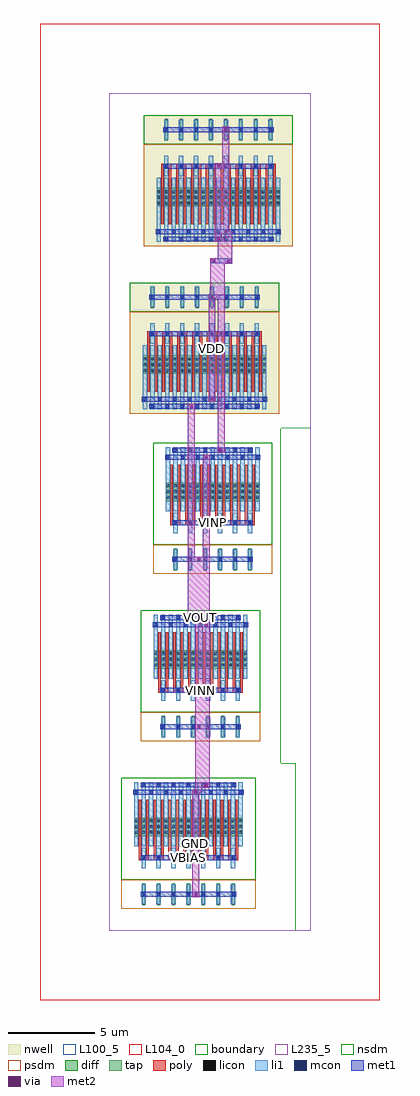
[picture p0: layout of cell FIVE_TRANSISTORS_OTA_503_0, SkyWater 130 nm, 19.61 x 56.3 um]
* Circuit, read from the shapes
.subckt FIVE_TRANSISTORS_OTA_503_0 GND VBIAS VDD VINN VINP VOUT
XM1 n1 VBIAS GND GND sky130_fd_pr__nfet_01v8 w=1.05 l=0.15 m=14
XM2 VOUT VINN n1 GND sky130_fd_pr__nfet_01v8 w=1.05 l=0.15 m=12
XM3 n2 VINP n1 GND sky130_fd_pr__nfet_01v8 w=1.05 l=0.15 m=12
XM4 VOUT n2 VDD VDD sky130_fd_pr__pfet_01v8 w=1.05 l=0.15 m=16
XM5 n2 n2 VDD VDD sky130_fd_pr__pfet_01v8 w=1.05 l=0.15 m=16
.ends

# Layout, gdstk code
from math import pi, radians
import gdstk
lib = gdstk.Library(unit=1e-6, precision=1e-09)
def R(c, l, rs):  # rectangles x0, y0, x1, y1
    for r in rs: c.add(gdstk.rectangle(r[:2], r[2:], *l))
def A(c, l, x, y, w, h, nx, ny, dx, dy):  # array of equal rectangles
    R(c, l, [(x+i*dx, y+j*dy, x+i*dx+w, y+j*dy+h) for i in range(nx) for j in range(ny)])
def P(c, l, *ps):  # polygons
    for p in ps: c.add(gdstk.Polygon(p, *l))
nwell = (64, 20)
diff = (65, 20)
tap = (65, 44)
poly = (66, 20)
licon = (66, 44)
li1 = (67, 20)
mcon = (67, 44)
met1 = (68, 20)
via = (68, 44)
met2 = (69, 20)
nsdm = (93, 44)
psdm = (94, 20)
L100_5 = (100, 5)
L104_0 = (104, 0)
boundary = (235, 4)
L235_5 = (235, 5)

dcl_pmos_s_4858765_x8_y1 = lib.new_cell('DCL_PMOS_S_4858765_X8_Y1_1746772025')
R(dcl_pmos_s_4858765_x8_y1, nwell, [(1.99,0.84,10.59,8.4)])
R(dcl_pmos_s_4858765_x8_y1, diff, [(2.725,3.15,9.855,4.2)])
A(dcl_pmos_s_4858765_x8_y1, tap, 3.195, 6.915, 0.17, 1.29, 8, 1, 0.86, 0)
A(dcl_pmos_s_4858765_x8_y1, poly, 2.99, 2.1, 0.15, 3.36, 16, 1, 0.43, 0)
A(dcl_pmos_s_4858765_x8_y1, poly, 2.99, 5.325, 0.58, 0.27, 8, 1, 0.86, 0)
A(dcl_pmos_s_4858765_x8_y1, licon, 2.765, 3.23, 0.17, 0.17, 3, 3, 0.43, 0.34)
A(dcl_pmos_s_4858765_x8_y1, licon, 3.625, 3.23, 0.17, 0.17, 3, 3, 0.43, 0.34)
A(dcl_pmos_s_4858765_x8_y1, licon, 4.485, 3.23, 0.17, 0.17, 3, 3, 0.43, 0.34)
A(dcl_pmos_s_4858765_x8_y1, licon, 5.345, 3.23, 0.17, 0.17, 3, 3, 0.43, 0.34)
A(dcl_pmos_s_4858765_x8_y1, licon, 6.205, 3.23, 0.17, 0.17, 3, 3, 0.43, 0.34)
A(dcl_pmos_s_4858765_x8_y1, licon, 7.065, 3.23, 0.17, 0.17, 3, 3, 0.43, 0.34)
A(dcl_pmos_s_4858765_x8_y1, licon, 7.925, 3.23, 0.17, 0.17, 3, 3, 0.43, 0.34)
A(dcl_pmos_s_4858765_x8_y1, licon, 8.785, 3.23, 0.17, 0.17, 3, 3, 0.43, 0.34)
A(dcl_pmos_s_4858765_x8_y1, licon, 3.195, 5.375, 0.17, 0.17, 8, 2, 0.86, 2.1)
A(dcl_pmos_s_4858765_x8_y1, li1, 2.725, 1.09, 0.25, 3.7, 17, 1, 0.43, 0)
A(dcl_pmos_s_4858765_x8_y1, li1, 3.155, 4.87, 0.25, 1.18, 8, 2, 0.86, 2.1)
A(dcl_pmos_s_4858765_x8_y1, mcon, 3.195, 1.175, 0.17, 0.17, 8, 2, 0.86, 4.2)
A(dcl_pmos_s_4858765_x8_y1, mcon, 2.765, 1.595, 0.17, 0.17, 9, 1, 0.86, 0)
A(dcl_pmos_s_4858765_x8_y1, mcon, 3.195, 7.475, 0.17, 0.17, 8, 1, 0.86, 0)
R(dcl_pmos_s_4858765_x8_y1, met1, [(3.11,1.12,9.47,1.4), (2.68,1.54,9.9,1.82), (3.11,5.32,9.47,5.6), (3.11,7.42,9.47,7.7)])
R(dcl_pmos_s_4858765_x8_y1, via, [(6.215,1.185,6.365,1.335), (6.645,1.605,6.795,1.755), (6.215,5.385,6.365,5.535), (6.645,7.485,6.795,7.635)])
R(dcl_pmos_s_4858765_x8_y1, met2, [(6.09,1.1,6.49,5.62), (6.52,1.52,6.92,7.72)])
R(dcl_pmos_s_4858765_x8_y1, nsdm, [(1.99,6.72,10.59,8.4)])
R(dcl_pmos_s_4858765_x8_y1, psdm, [(1.99,0.84,10.59,6.72)])
R(dcl_pmos_s_4858765_x8_y1, L100_5, [(0,0,11.61,9.66)])
R(dcl_pmos_s_4858765_x8_y1, boundary, [(0,0,11.61,9.66)])

nmos_s_90315311_x7_y1_17 = lib.new_cell('NMOS_S_90315311_X7_Y1_1746772028')
R(nmos_s_90315311_x7_y1_17, diff, [(1.425,3.15,7.695,4.2)])
A(nmos_s_90315311_x7_y1_17, tap, 1.895, 6.915, 0.17, 1.29, 7, 1, 0.86, 0)
A(nmos_s_90315311_x7_y1_17, poly, 1.69, 2.1, 0.15, 3.36, 14, 1, 0.43, 0)
A(nmos_s_90315311_x7_y1_17, poly, 1.69, 5.325, 0.58, 0.27, 7, 1, 0.86, 0)
A(nmos_s_90315311_x7_y1_17, licon, 1.465, 3.23, 0.17, 0.17, 3, 3, 0.43, 0.34)
A(nmos_s_90315311_x7_y1_17, licon, 2.325, 3.23, 0.17, 0.17, 3, 3, 0.43, 0.34)
A(nmos_s_90315311_x7_y1_17, licon, 3.185, 3.23, 0.17, 0.17, 3, 3, 0.43, 0.34)
A(nmos_s_90315311_x7_y1_17, licon, 4.045, 3.23, 0.17, 0.17, 3, 3, 0.43, 0.34)
A(nmos_s_90315311_x7_y1_17, licon, 4.905, 3.23, 0.17, 0.17, 3, 3, 0.43, 0.34)
A(nmos_s_90315311_x7_y1_17, licon, 5.765, 3.23, 0.17, 0.17, 3, 3, 0.43, 0.34)
A(nmos_s_90315311_x7_y1_17, licon, 6.625, 3.23, 0.17, 0.17, 3, 3, 0.43, 0.34)
A(nmos_s_90315311_x7_y1_17, licon, 1.895, 5.375, 0.17, 0.17, 7, 2, 0.86, 2.1)
A(nmos_s_90315311_x7_y1_17, li1, 1.425, 1.09, 0.25, 3.7, 15, 1, 0.43, 0)
A(nmos_s_90315311_x7_y1_17, li1, 1.855, 4.87, 0.25, 1.18, 7, 2, 0.86, 2.1)
A(nmos_s_90315311_x7_y1_17, mcon, 1.895, 1.175, 0.17, 0.17, 7, 2, 0.86, 4.2)
A(nmos_s_90315311_x7_y1_17, mcon, 1.465, 1.595, 0.17, 0.17, 8, 1, 0.86, 0)
A(nmos_s_90315311_x7_y1_17, mcon, 1.895, 7.475, 0.17, 0.17, 7, 1, 0.86, 0)
R(nmos_s_90315311_x7_y1_17, met1, [(1.81,1.12,7.31,1.4), (1.38,1.54,7.74,1.82), (1.81,5.32,7.31,5.6), (1.81,7.42,7.31,7.7)])
R(nmos_s_90315311_x7_y1_17, via, [(4.915,1.605,5.065,1.755), (4.915,7.485,5.065,7.635)])
R(nmos_s_90315311_x7_y1_17, met2, [(4.79,1.52,5.19,7.72)])
R(nmos_s_90315311_x7_y1_17, nsdm, [(0.69,0.84,8.43,6.72)])
R(nmos_s_90315311_x7_y1_17, psdm, [(0.69,6.72,8.43,8.4)])
R(nmos_s_90315311_x7_y1_17, L100_5, [(0,0,10.75,9.66)])
R(nmos_s_90315311_x7_y1_17, boundary, [(0,0,10.75,9.66)])

pmos_s_52407068_x8_y1_17 = lib.new_cell('PMOS_S_52407068_X8_Y1_1746772029')
R(pmos_s_52407068_x8_y1_17, nwell, [(1.19,0.84,9.79,8.4)])
R(pmos_s_52407068_x8_y1_17, diff, [(1.925,3.15,9.055,4.2)])
A(pmos_s_52407068_x8_y1_17, tap, 2.395, 6.915, 0.17, 1.29, 8, 1, 0.86, 0)
A(pmos_s_52407068_x8_y1_17, poly, 2.19, 2.1, 0.15, 3.36, 16, 1, 0.43, 0)
A(pmos_s_52407068_x8_y1_17, poly, 2.19, 5.325, 0.58, 0.27, 8, 1, 0.86, 0)
A(pmos_s_52407068_x8_y1_17, licon, 1.965, 3.23, 0.17, 0.17, 3, 3, 0.43, 0.34)
A(pmos_s_52407068_x8_y1_17, licon, 2.825, 3.23, 0.17, 0.17, 3, 3, 0.43, 0.34)
A(pmos_s_52407068_x8_y1_17, licon, 3.685, 3.23, 0.17, 0.17, 3, 3, 0.43, 0.34)
A(pmos_s_52407068_x8_y1_17, licon, 4.545, 3.23, 0.17, 0.17, 3, 3, 0.43, 0.34)
A(pmos_s_52407068_x8_y1_17, licon, 5.405, 3.23, 0.17, 0.17, 3, 3, 0.43, 0.34)
A(pmos_s_52407068_x8_y1_17, licon, 6.265, 3.23, 0.17, 0.17, 3, 3, 0.43, 0.34)
A(pmos_s_52407068_x8_y1_17, licon, 7.125, 3.23, 0.17, 0.17, 3, 3, 0.43, 0.34)
A(pmos_s_52407068_x8_y1_17, licon, 7.985, 3.23, 0.17, 0.17, 3, 3, 0.43, 0.34)
A(pmos_s_52407068_x8_y1_17, licon, 2.395, 5.375, 0.17, 0.17, 8, 2, 0.86, 2.1)
A(pmos_s_52407068_x8_y1_17, li1, 1.925, 1.09, 0.25, 3.7, 17, 1, 0.43, 0)
A(pmos_s_52407068_x8_y1_17, li1, 2.355, 4.87, 0.25, 1.18, 8, 2, 0.86, 2.1)
A(pmos_s_52407068_x8_y1_17, mcon, 2.395, 1.175, 0.17, 0.17, 8, 2, 0.86, 4.2)
A(pmos_s_52407068_x8_y1_17, mcon, 1.965, 1.595, 0.17, 0.17, 9, 1, 0.86, 0)
A(pmos_s_52407068_x8_y1_17, mcon, 2.395, 7.475, 0.17, 0.17, 8, 1, 0.86, 0)
R(pmos_s_52407068_x8_y1_17, met1, [(2.31,1.12,8.67,1.4), (1.88,1.54,9.1,1.82), (2.31,5.32,8.67,5.6), (2.31,7.42,8.67,7.7)])
R(pmos_s_52407068_x8_y1_17, via, [(5.845,1.605,5.995,1.755), (5.845,7.485,5.995,7.635)])
R(pmos_s_52407068_x8_y1_17, met2, [(5.72,1.52,6.12,7.72)])
R(pmos_s_52407068_x8_y1_17, nsdm, [(1.19,6.72,9.79,8.4)])
R(pmos_s_52407068_x8_y1_17, psdm, [(1.19,0.84,9.79,6.72)])
R(pmos_s_52407068_x8_y1_17, L100_5, [(0,0,11.61,9.66)])
R(pmos_s_52407068_x8_y1_17, boundary, [(0,0,11.61,9.66)])

nmos_4t_54711865_x6_y1_1 = lib.new_cell('NMOS_4T_54711865_X6_Y1_1746772027')
R(nmos_4t_54711865_x6_y1_1, diff, [(1.925,3.15,7.335,4.2)])
A(nmos_4t_54711865_x6_y1_1, tap, 2.395, 6.915, 0.17, 1.29, 6, 1, 0.86, 0)
A(nmos_4t_54711865_x6_y1_1, poly, 2.19, 2.1, 0.15, 3.36, 12, 1, 0.43, 0)
A(nmos_4t_54711865_x6_y1_1, poly, 2.19, 5.325, 0.58, 0.27, 6, 1, 0.86, 0)
A(nmos_4t_54711865_x6_y1_1, licon, 1.965, 3.23, 0.17, 0.17, 3, 3, 0.43, 0.34)
A(nmos_4t_54711865_x6_y1_1, licon, 2.825, 3.23, 0.17, 0.17, 3, 3, 0.43, 0.34)
A(nmos_4t_54711865_x6_y1_1, licon, 3.685, 3.23, 0.17, 0.17, 3, 3, 0.43, 0.34)
A(nmos_4t_54711865_x6_y1_1, licon, 4.545, 3.23, 0.17, 0.17, 3, 3, 0.43, 0.34)
A(nmos_4t_54711865_x6_y1_1, licon, 5.405, 3.23, 0.17, 0.17, 3, 3, 0.43, 0.34)
A(nmos_4t_54711865_x6_y1_1, licon, 6.265, 3.23, 0.17, 0.17, 3, 3, 0.43, 0.34)
A(nmos_4t_54711865_x6_y1_1, licon, 2.395, 5.375, 0.17, 0.17, 6, 2, 0.86, 2.1)
A(nmos_4t_54711865_x6_y1_1, li1, 1.925, 1.09, 0.25, 3.7, 13, 1, 0.43, 0)
A(nmos_4t_54711865_x6_y1_1, li1, 2.355, 4.87, 0.25, 1.18, 6, 2, 0.86, 2.1)
A(nmos_4t_54711865_x6_y1_1, mcon, 2.395, 1.175, 0.17, 0.17, 6, 2, 0.86, 4.2)
A(nmos_4t_54711865_x6_y1_1, mcon, 1.965, 1.595, 0.17, 0.17, 7, 1, 0.86, 0)
A(nmos_4t_54711865_x6_y1_1, mcon, 2.395, 7.475, 0.17, 0.17, 6, 1, 0.86, 0)
R(nmos_4t_54711865_x6_y1_1, met1, [(2.31,1.12,6.95,1.4), (1.88,1.54,7.38,1.82), (2.31,5.32,6.95,5.6), (2.31,7.42,6.95,7.7)])
R(nmos_4t_54711865_x6_y1_1, nsdm, [(1.19,0.84,8.07,6.72)])
R(nmos_4t_54711865_x6_y1_1, psdm, [(1.19,6.72,8.07,8.4)])
R(nmos_4t_54711865_x6_y1_1, L100_5, [(0,0,9.89,9.66)])
R(nmos_4t_54711865_x6_y1_1, boundary, [(0,0,9.89,9.66)])

nmos_4t_34129767_x6_y1_1 = lib.new_cell('NMOS_4T_34129767_X6_Y1_1746772026')
R(nmos_4t_34129767_x6_y1_1, diff, [(1.225,3.15,6.635,4.2)])
A(nmos_4t_34129767_x6_y1_1, tap, 1.695, 6.915, 0.17, 1.29, 6, 1, 0.86, 0)
A(nmos_4t_34129767_x6_y1_1, poly, 1.49, 2.1, 0.15, 3.36, 12, 1, 0.43, 0)
A(nmos_4t_34129767_x6_y1_1, poly, 1.49, 5.325, 0.58, 0.27, 6, 1, 0.86, 0)
A(nmos_4t_34129767_x6_y1_1, licon, 1.265, 3.23, 0.17, 0.17, 3, 3, 0.43, 0.34)
A(nmos_4t_34129767_x6_y1_1, licon, 2.125, 3.23, 0.17, 0.17, 3, 3, 0.43, 0.34)
A(nmos_4t_34129767_x6_y1_1, licon, 2.985, 3.23, 0.17, 0.17, 3, 3, 0.43, 0.34)
A(nmos_4t_34129767_x6_y1_1, licon, 3.845, 3.23, 0.17, 0.17, 3, 3, 0.43, 0.34)
A(nmos_4t_34129767_x6_y1_1, licon, 4.705, 3.23, 0.17, 0.17, 3, 3, 0.43, 0.34)
A(nmos_4t_34129767_x6_y1_1, licon, 5.565, 3.23, 0.17, 0.17, 3, 3, 0.43, 0.34)
A(nmos_4t_34129767_x6_y1_1, licon, 1.695, 5.375, 0.17, 0.17, 6, 2, 0.86, 2.1)
A(nmos_4t_34129767_x6_y1_1, li1, 1.225, 1.09, 0.25, 3.7, 13, 1, 0.43, 0)
A(nmos_4t_34129767_x6_y1_1, li1, 1.655, 4.87, 0.25, 1.18, 6, 2, 0.86, 2.1)
A(nmos_4t_34129767_x6_y1_1, mcon, 1.695, 1.175, 0.17, 0.17, 6, 2, 0.86, 4.2)
A(nmos_4t_34129767_x6_y1_1, mcon, 1.265, 1.595, 0.17, 0.17, 7, 1, 0.86, 0)
A(nmos_4t_34129767_x6_y1_1, mcon, 1.695, 7.475, 0.17, 0.17, 6, 1, 0.86, 0)
R(nmos_4t_34129767_x6_y1_1, met1, [(1.61,1.12,6.25,1.4), (1.18,1.54,6.68,1.82), (1.61,5.32,6.25,5.6), (1.61,7.42,6.25,7.7)])
R(nmos_4t_34129767_x6_y1_1, nsdm, [(0.49,0.84,7.37,6.72)])
R(nmos_4t_34129767_x6_y1_1, psdm, [(0.49,6.72,7.37,8.4)])
R(nmos_4t_34129767_x6_y1_1, L100_5, [(0,0,9.89,9.66)])
R(nmos_4t_34129767_x6_y1_1, boundary, [(0,0,9.89,9.66)])

five_transistors_ota_503 = lib.new_cell('FIVE_TRANSISTORS_OTA_503_0')
R(five_transistors_ota_503, met1, [(5.43,8.26,5.75,8.54), (5.43,8.26,5.75,8.54), (5.43,8.26,5.75,8.54), (5.43,8.26,5.75,8.54), (5,11.62,5.32,11.9), (5,11.62,5.32,11.9), (5,11.62,5.32,11.9), (5,11.62,5.32,11.9), (5.43,17.5,5.75,17.78), (5.43,17.5,5.75,17.78), (5.43,17.5,5.75,17.78), (5.43,17.5,5.75,17.78), (4.57,17.92,4.89,18.2), (4.57,17.92,4.89,18.2), (5,21.28,5.32,21.56), (5,21.28,5.32,21.56), (5.43,27.16,5.75,27.44), (5.43,27.16,5.75,27.44), (6.29,27.58,6.61,27.86), (6.29,27.58,6.61,27.86), (6.29,27.58,6.61,27.86), (6.29,27.58,6.61,27.86), (4.57,30.1,4.89,30.38), (4.57,30.1,4.89,30.38), (6.29,34.3,6.61,34.58), (6.29,34.3,6.61,34.58), (6.29,34.3,6.61,34.58), (6.29,34.3,6.61,34.58), (5.86,38.5,6.18,38.78), (5.86,38.5,6.18,38.78), (6.02,38.5,6.88,38.78), (6.72,38.5,7.04,38.78), (6.72,38.5,7.04,38.78)])
P(five_transistors_ota_503, met1, [(0,0),(0,0),(0,0),(0,0)],
  [(0,0),(0,0),(0,0),(0,0)],
  [(0,0),(0,0),(0,0),(0,0)],
  [(0,0),(0,0),(0,0),(0,0)],
  [(0,0),(0,0),(0,0),(0,0)],
  [(0,0),(0,0),(0,0),(0,0)],
  [(0,0),(0,0),(0,0),(0,0)],
  [(0,0),(0,0),(0,0),(0,0)],
  [(0,0),(0,0),(0,0),(0,0)],
  [(0,0),(0,0),(0,0),(0,0)],
  [(0,0),(0,0),(0,0),(0,0)],
  [(0,0),(0,0),(0,0),(0,0)],
  [(0,0),(0,0),(0,0),(0,0)],
  [(0,0),(0,0),(0,0),(0,0)],
  [(0,0),(0,0),(0,0),(0,0)],
  [(0,0),(0,0),(0,0),(0,0)])
R(five_transistors_ota_503, via, [(5.515,8.325,5.665,8.475), (5.515,8.325,5.665,8.475), (5.515,8.325,5.665,8.475), (5.515,8.325,5.665,8.475), (5.085,11.685,5.235,11.835), (5.085,11.685,5.235,11.835), (5.085,11.685,5.235,11.835), (5.085,11.685,5.235,11.835), (5.515,17.565,5.665,17.715), (5.515,17.565,5.665,17.715), (5.515,17.565,5.665,17.715), (5.515,17.565,5.665,17.715), (4.655,17.985,4.805,18.135), (4.655,17.985,4.805,18.135), (5.085,21.345,5.235,21.495), (5.085,21.345,5.235,21.495), (5.515,27.225,5.665,27.375), (5.515,27.225,5.665,27.375), (6.375,27.645,6.525,27.795), (6.375,27.645,6.525,27.795), (6.375,27.645,6.525,27.795), (6.375,27.645,6.525,27.795), (4.655,30.165,4.805,30.315), (4.655,30.165,4.805,30.315), (6.375,34.365,6.525,34.515), (6.375,34.365,6.525,34.515), (6.375,34.365,6.525,34.515), (6.375,34.365,6.525,34.515), (5.945,38.565,6.095,38.715), (5.945,38.565,6.095,38.715), (6.805,38.565,6.955,38.715), (6.805,38.565,6.955,38.715)])
R(five_transistors_ota_503, met2, [(4.96,7.98,5.36,11.76), (5.39,8.24,5.79,8.56), (5.39,8.24,5.79,8.56), (5.39,8.24,5.79,8.56), (5.39,8.24,5.79,8.56), (5.39,8.4,5.79,17.64), (4.96,11.6,5.36,11.92), (4.96,11.6,5.36,11.92), (4.96,11.6,5.36,11.92), (4.96,11.6,5.36,11.92), (4.96,11.76,5.36,21.42), (5.39,17.48,5.79,17.8), (5.39,17.48,5.79,17.8), (5.39,17.48,5.79,17.8), (5.39,17.48,5.79,17.8), (5.39,17.64,5.79,27.3), (4.53,17.9,4.93,18.22), (4.53,17.9,4.93,18.22), (4.53,18.06,4.93,30.24), (4.96,21.26,5.36,21.58), (4.96,21.26,5.36,21.58), (5.39,27.14,5.79,27.46), (5.39,27.14,5.79,27.46), (6.25,27.56,6.65,27.88), (6.25,27.56,6.65,27.88), (6.25,27.56,6.65,27.88), (6.25,27.56,6.65,27.88), (6.25,27.72,6.65,34.44), (4.53,30.08,4.93,30.4), (4.53,30.08,4.93,30.4), (6.25,34.28,6.65,34.6), (6.25,34.28,6.65,34.6), (6.25,34.28,6.65,34.6), (6.25,34.28,6.65,34.6), (6.25,34.44,6.65,39.9), (5.82,36.54,6.22,38.64), (5.82,38.48,6.22,38.8), (5.82,38.48,6.22,38.8), (6.68,38.48,7.08,38.8), (6.68,38.48,7.08,38.8), (6.68,38.64,7.08,40.32)])
P(five_transistors_ota_503, met2, [(0,0),(0,0),(0,0),(0,0)],
  [(0,0),(0,0),(0,0),(0,0)],
  [(0,0),(0,0),(0,0),(0,0)],
  [(0,0),(0,0),(0,0),(0,0)],
  [(0,0),(0,0),(0,0),(0,0)],
  [(0,0),(0,0),(0,0),(0,0)])
R(five_transistors_ota_503, L104_0, [(-4,-4,15.61,52.3)])
R(five_transistors_ota_503, L235_5, [(0,0,11.61,48.3)])
five_transistors_ota_503.add(gdstk.Reference(dcl_pmos_s_4858765_x8_y1, (0,38.64)))
five_transistors_ota_503.add(gdstk.Reference(nmos_s_90315311_x7_y1_17, (0,9.66), x_reflection=True))
five_transistors_ota_503.add(gdstk.Reference(pmos_s_52407068_x8_y1_17, (0,28.98)))
five_transistors_ota_503.add(gdstk.Reference(nmos_4t_54711865_x6_y1_1, (9.89,19.32), rotation=pi))
five_transistors_ota_503.add(gdstk.Reference(nmos_4t_34129767_x6_y1_1, (9.89,28.98), rotation=pi))
five_transistors_ota_503.add(gdstk.Label('VDD', (5.92,33.6), layer=69, texttype=5))
five_transistors_ota_503.add(gdstk.Label('VBIAS', (4.56,4.2), layer=68, texttype=5))
five_transistors_ota_503.add(gdstk.Label('GND', (4.99,5.04), layer=69, texttype=5))
five_transistors_ota_503.add(gdstk.Label('VOUT', (5.26,18.06), layer=68, texttype=5))
five_transistors_ota_503.add(gdstk.Label('VINN', (5.26,13.86), layer=68, texttype=5))
five_transistors_ota_503.add(gdstk.Label('VINP', (5.96,23.52), layer=68, texttype=5))

lib.write_gds('FIVE_TRANSISTORS_OTA_503_0.gds')
